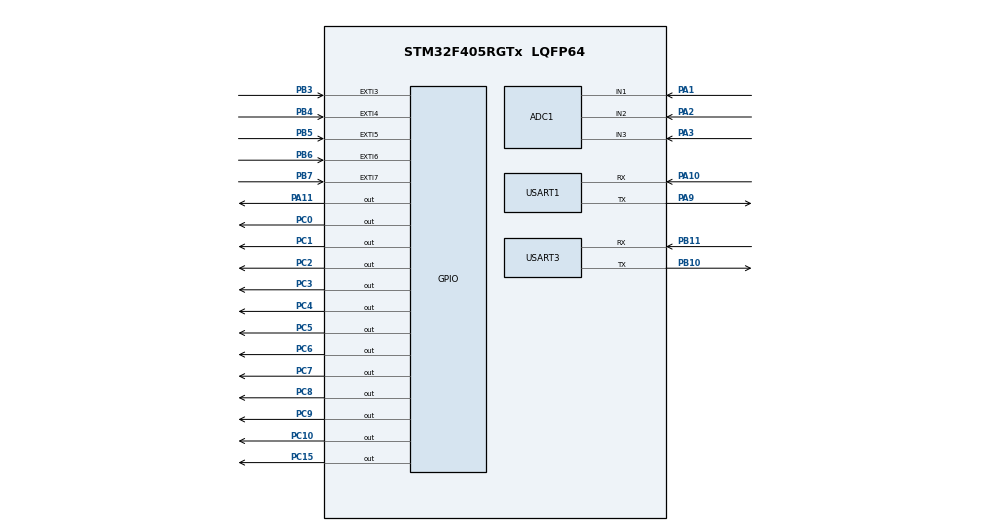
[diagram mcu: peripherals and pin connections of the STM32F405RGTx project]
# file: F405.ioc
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ADC1.Channel-0\#ChannelRegularConversion=ADC_CHANNEL_1
ADC1.ExternalTrigConv=ADC_EXTERNALTRIGCONV_T3_TRGO
ADC1.NbrOfConversionFlag=1
ADC1.Rank-0\#ChannelRegularConversion=1
ADC1.SamplingTime-0\#ChannelRegularConversion=ADC_SAMPLETIME_3CYCLES
ADC1.ScanConvMode=ENABLE
ADC1.master=1
Dma.ADC1.0.Direction=DMA_PERIPH_TO_MEMORY
Dma.ADC1.0.FIFOMode=DMA_FIFOMODE_DISABLE
Dma.ADC1.0.Instance=DMA2_Stream0
Dma.ADC1.0.MemDataAlignment=DMA_MDATAALIGN_HALFWORD
Dma.ADC1.0.MemInc=DMA_MINC_ENABLE
Dma.ADC1.0.Mode=DMA_NORMAL
Dma.ADC1.0.PeriphDataAlignment=DMA_PDATAALIGN_HALFWORD
Dma.ADC1.0.PeriphInc=DMA_PINC_DISABLE
Dma.ADC1.0.Priority=DMA_PRIORITY_LOW
Dma.Request0=ADC1
Mcu.Family=STM32F4
Mcu.Name=STM32F405RGTx
Mcu.Package=LQFP64
NVIC.DMA2_Stream0_IRQn=true\:0\:0\:false\:false\:true\:false\:true\:true
NVIC.PriorityGroup=NVIC_PRIORITYGROUP_4
PA1.Signal=ADCx_IN1
PA10.Mode=Asynchronous
PA10.Signal=USART1_RX
PA11.Signal=GPIO_Output
PA13.Mode=Serial_Wire
PA13.Signal=SYS_JTMS-SWDIO
PA14.Mode=Serial_Wire
PA14.Signal=SYS_JTCK-SWCLK
PA2.Signal=ADCx_IN2
PA3.Signal=ADCx_IN3
PA9.Mode=Asynchronous
PA9.Signal=USART1_TX
PB10.Mode=Asynchronous
PB10.Signal=USART3_TX
PB11.Mode=Asynchronous
PB11.Signal=USART3_RX
PB3.Signal=GPXTI3
PB4.Signal=GPXTI4
PB5.Signal=GPXTI5
PB6.Signal=GPXTI6
PB7.Signal=GPXTI7
PC0.Signal=GPIO_Output
PC1.Signal=GPIO_Output
PC10.Signal=GPIO_Output
PC15-OSC32_OUT.Signal=GPIO_Output
PC2.Signal=GPIO_Output
PC3.Signal=GPIO_Output
PC4.Signal=GPIO_Output
PC5.Signal=GPIO_Output
PC6.Signal=GPIO_Output
PC7.Signal=GPIO_Output
PC8.Signal=GPIO_Output
PC9.Signal=GPIO_Output
ProjectManager.HeapSize=0x200
ProjectManager.StackSize=0x400
ProjectManager.TargetToolchain=STM32CubeIDE
RCC.48MHZClocksFreq_Value=84000000
RCC.AHBFreq_Value=168000000
RCC.APB1CLKDivider=RCC_HCLK_DIV4
RCC.APB1Freq_Value=42000000
RCC.APB1TimFreq_Value=84000000
RCC.APB2CLKDivider=RCC_HCLK_DIV2
RCC.APB2Freq_Value=84000000
RCC.APB2TimFreq_Value=168000000
RCC.CortexFreq_Value=168000000
RCC.HCLKFreq_Value=168000000
RCC.HSE_VALUE=25000000
RCC.HSI_VALUE=16000000
RCC.LSE_VALUE=32768
RCC.PLLM=8
RCC.PLLN=168
RCC.SYSCLKFreq_VALUE=168000000
RCC.SYSCLKSource=RCC_SYSCLKSOURCE_PLLCLK
RCC.VCOOutputFreq_Value=336000000
SH.ADCx_IN1.0=ADC1_IN1,IN1
SH.ADCx_IN2.0=ADC1_IN2,IN2
SH.ADCx_IN3.0=ADC3_IN3
SH.ADCx_IN3.1=ADC1_IN3,IN3
TIM3.Channel-Output\ Compare1\ No\ Output=TIM_CHANNEL_1
USART1.VirtualMode=VM_ASYNC
USART3.VirtualMode=VM_ASYNC
VP_TIM3_VS_no_output1.Mode=Output Compare1 No Output
VP_TIM7_VS_ClockSourceINT.Mode=Enable_Timer
VP_TIM7_VS_OPM.Mode=OPM_bit
board=custom

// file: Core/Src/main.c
/* USER CODE BEGIN Header */
/**
 ******************************************************************************
 * @file           : main.c
 * @brief          : Main program body
 ******************************************************************************
 * @attention
 *
 * Copyright (c) 2023 STMicroelectronics.
 * All rights reserved.
 *
 * This software is licensed under terms that can be found in the LICENSE file
 * in the root directory of this software component.
 * If no LICENSE file comes with this software, it is provided AS-IS.
 *
 ******************************************************************************
 */
/* USER CODE END Header */
#include "main.h"

#include "Display/display.h"
/* USER CODE BEGIN Includes */
#include "MoveControl/movecontrol.h"
#include "Modbus/modbus.h"
#include "Settings/Settings.h"
#include "VibroSens/vibro.h"
/* USER CODE END Includes */

ADC_HandleTypeDef hadc1;
DMA_HandleTypeDef hdma_adc1;

TIM_HandleTypeDef htim3;
TIM_HandleTypeDef htim7;

UART_HandleTypeDef huart1;
UART_HandleTypeDef huart3;

void SystemClock_Config(void);
static void MX_GPIO_Init(void);
static void MX_DMA_Init(void);
static void MX_USART1_UART_Init(void);
static void MX_USART3_UART_Init(void);
static void MX_ADC1_Init(void);
static void MX_TIM3_Init(void);
static void MX_TIM7_Init(void);

int main(void)
{

	/* MCU Configuration--------------------------------------------------------*/

	/* Reset of all peripherals, Initializes the Flash interface and the Systick. */
	HAL_Init();

	/* Configure the system clock */
	SystemClock_Config();

	/* Initialize all configured peripherals */
	MX_GPIO_Init();
	MX_DMA_Init();
	MX_USART1_UART_Init();
	MX_USART3_UART_Init();
	MX_ADC1_Init();
	MX_TIM3_Init();
	MX_TIM7_Init();
	/* USER CODE BEGIN 2 */

	ModBusInit();
	InitMotors();
	LCD1602_Init();
	ReadSettings();
	InitVibro();
	//Старт АЦП
	/* USER CODE END 2 */

	/* Infinite loop */
	/* USER CODE BEGIN WHILE */
	while (1)
	{
		DisplayProc(); //Регистрация нажатия кнопок и вывод инфы
		VibroProc();   //Обработка с датчиков и анализ скорости
		MotorsControlProc(); //Работа с частотниками в соотвеститвии с настрйоками и анализа с датчиков
		/* USER CODE END WHILE */

	}
}

void SystemClock_Config(void)
{
	RCC_OscInitTypeDef RCC_OscInitStruct = {0};
	RCC_ClkInitTypeDef RCC_ClkInitStruct = {0};

	/** Configure the main internal regulator output voltage
	 */
	__HAL_RCC_PWR_CLK_ENABLE();
	__HAL_PWR_VOLTAGESCALING_CONFIG(PWR_REGULATOR_VOLTAGE_SCALE1);

	/** Initializes the RCC Oscillators according to the specified parameters
	 * in the RCC_OscInitTypeDef structure.
	 */
	RCC_OscInitStruct.OscillatorType = RCC_OSCILLATORTYPE_HSI;
	RCC_OscInitStruct.HSIState = RCC_HSI_ON;
	RCC_OscInitStruct.HSICalibrationValue = RCC_HSICALIBRATION_DEFAULT;
	RCC_OscInitStruct.PLL.PLLState = RCC_PLL_NONE;
	if (HAL_RCC_OscConfig(&RCC_OscInitStruct) != HAL_OK)
	{
		Error_Handler();
	}

	/** Initializes the CPU, AHB and APB buses clocks
	 */
	RCC_ClkInitStruct.ClockType = RCC_CLOCKTYPE_HCLK|RCC_CLOCKTYPE_SYSCLK
			|RCC_CLOCKTYPE_PCLK1|RCC_CLOCKTYPE_PCLK2;
	RCC_ClkInitStruct.SYSCLKSource = RCC_SYSCLKSOURCE_HSI;
	RCC_ClkInitStruct.AHBCLKDivider = RCC_SYSCLK_DIV1;
	RCC_ClkInitStruct.APB1CLKDivider = RCC_HCLK_DIV1;
	RCC_ClkInitStruct.APB2CLKDivider = RCC_HCLK_DIV1;

	if (HAL_RCC_ClockConfig(&RCC_ClkInitStruct, FLASH_LATENCY_0) != HAL_OK)
	{
		Error_Handler();
	}
}

static void MX_ADC1_Init(void)
{

	ADC_ChannelConfTypeDef sConfig = {0};

	/** Configure the global features of the ADC (Clock, Resolution, Data Alignment and number of conversion)
	 */
	hadc1.Instance = ADC1;
	hadc1.Init.ClockPrescaler = ADC_CLOCK_SYNC_PCLK_DIV2;
	hadc1.Init.Resolution = ADC_RESOLUTION_12B;
	hadc1.Init.ScanConvMode = ENABLE;
	hadc1.Init.ContinuousConvMode = DISABLE;
	hadc1.Init.DiscontinuousConvMode = DISABLE;
	hadc1.Init.ExternalTrigConvEdge = ADC_EXTERNALTRIGCONVEDGE_RISING;
	hadc1.Init.ExternalTrigConv = ADC_EXTERNALTRIGCONV_T3_TRGO;
	hadc1.Init.DataAlign = ADC_DATAALIGN_RIGHT;
	hadc1.Init.NbrOfConversion = 1;
	hadc1.Init.DMAContinuousRequests = DISABLE;
	hadc1.Init.EOCSelection = ADC_EOC_SINGLE_CONV;
	if (HAL_ADC_Init(&hadc1) != HAL_OK)
	{
		Error_Handler();
	}

	/** Configure for the selected ADC regular channel its corresponding rank in the sequencer and its sample time.
	 */
	sConfig.Channel = ADC_CHANNEL_1;
	sConfig.Rank = 1;
	sConfig.SamplingTime = ADC_SAMPLETIME_3CYCLES;
	if (HAL_ADC_ConfigChannel(&hadc1, &sConfig) != HAL_OK)
	{
		Error_Handler();
	}

}

static void MX_TIM3_Init(void)
{

	TIM_MasterConfigTypeDef sMasterConfig = {0};
	TIM_OC_InitTypeDef sConfigOC = {0};

	htim3.Instance = TIM3;
	htim3.Init.Prescaler = 0;
	htim3.Init.CounterMode = TIM_COUNTERMODE_UP;
	htim3.Init.Period = 65535;
	htim3.Init.ClockDivision = TIM_CLOCKDIVISION_DIV1;
	htim3.Init.AutoReloadPreload = TIM_AUTORELOAD_PRELOAD_DISABLE;
	if (HAL_TIM_OC_Init(&htim3) != HAL_OK)
	{
		Error_Handler();
	}
	sMasterConfig.MasterOutputTrigger = TIM_TRGO_RESET;
	sMasterConfig.MasterSlaveMode = TIM_MASTERSLAVEMODE_DISABLE;
	if (HAL_TIMEx_MasterConfigSynchronization(&htim3, &sMasterConfig) != HAL_OK)
	{
		Error_Handler();
	}
	sConfigOC.OCMode = TIM_OCMODE_TIMING;
	sConfigOC.Pulse = 0;
	sConfigOC.OCPolarity = TIM_OCPOLARITY_HIGH;
	sConfigOC.OCFastMode = TIM_OCFAST_DISABLE;
	if (HAL_TIM_OC_ConfigChannel(&htim3, &sConfigOC, TIM_CHANNEL_1) != HAL_OK)
	{
		Error_Handler();
	}

}

static void MX_TIM7_Init(void)
{

	TIM_MasterConfigTypeDef sMasterConfig = {0};

	htim7.Instance = TIM7;
	htim7.Init.Prescaler = 0;
	htim7.Init.CounterMode = TIM_COUNTERMODE_UP;
	htim7.Init.Period = 65535;
	htim7.Init.AutoReloadPreload = TIM_AUTORELOAD_PRELOAD_DISABLE;
	if (HAL_TIM_Base_Init(&htim7) != HAL_OK)
	{
		Error_Handler();
	}
	if (HAL_TIM_OnePulse_Init(&htim7, TIM_OPMODE_SINGLE) != HAL_OK)
	{
		Error_Handler();
	}
	sMasterConfig.MasterOutputTrigger = TIM_TRGO_RESET;
	sMasterConfig.MasterSlaveMode = TIM_MASTERSLAVEMODE_DISABLE;
	if (HAL_TIMEx_MasterConfigSynchronization(&htim7, &sMasterConfig) != HAL_OK)
	{
		Error_Handler();
	}

}

static void MX_USART1_UART_Init(void)
{

	huart1.Instance = USART1;
	huart1.Init.BaudRate = 115200;
	huart1.Init.WordLength = UART_WORDLENGTH_8B;
	huart1.Init.StopBits = UART_STOPBITS_1;
	huart1.Init.Parity = UART_PARITY_NONE;
	huart1.Init.Mode = UART_MODE_TX_RX;
	huart1.Init.HwFlowCtl = UART_HWCONTROL_NONE;
	huart1.Init.OverSampling = UART_OVERSAMPLING_16;
	if (HAL_UART_Init(&huart1) != HAL_OK)
	{
		Error_Handler();
	}

}

static void MX_USART3_UART_Init(void)
{

	huart3.Instance = USART3;
	huart3.Init.BaudRate = 115200;
	huart3.Init.WordLength = UART_WORDLENGTH_8B;
	huart3.Init.StopBits = UART_STOPBITS_1;
	huart3.Init.Parity = UART_PARITY_NONE;
	huart3.Init.Mode = UART_MODE_TX_RX;
	huart3.Init.HwFlowCtl = UART_HWCONTROL_NONE;
	huart3.Init.OverSampling = UART_OVERSAMPLING_16;
	if (HAL_UART_Init(&huart3) != HAL_OK)
	{
		Error_Handler();
	}

}

static void MX_DMA_Init(void)
{

	/* DMA controller clock enable */
	__HAL_RCC_DMA2_CLK_ENABLE();

	/* DMA interrupt init */
	/* DMA2_Stream0_IRQn interrupt configuration */
	HAL_NVIC_SetPriority(DMA2_Stream0_IRQn, 0, 0);
	HAL_NVIC_EnableIRQ(DMA2_Stream0_IRQn);

}

static void MX_GPIO_Init(void)
{
	GPIO_InitTypeDef GPIO_InitStruct = {0};

	/* GPIO Ports Clock Enable */
	__HAL_RCC_GPIOC_CLK_ENABLE();
	__HAL_RCC_GPIOA_CLK_ENABLE();
	__HAL_RCC_GPIOB_CLK_ENABLE();

	/*Configure GPIO pin Output Level */
	HAL_GPIO_WritePin(GPIOC, GPIO_PIN_15|GPIO_PIN_0|GPIO_PIN_1|GPIO_PIN_2
			|GPIO_PIN_3|GPIO_PIN_4|GPIO_PIN_5|GPIO_PIN_6
			|GPIO_PIN_7|GPIO_PIN_8|GPIO_PIN_9|GPIO_PIN_10, GPIO_PIN_RESET);

	/*Configure GPIO pin Output Level */
	HAL_GPIO_WritePin(GPIOA, GPIO_PIN_11, GPIO_PIN_RESET);

	/*Configure GPIO pins : PC15 PC0 PC1 PC2
                           PC3 PC4 PC5 PC6
                           PC7 PC8 PC9 PC10 */
	GPIO_InitStruct.Pin = GPIO_PIN_15|GPIO_PIN_0|GPIO_PIN_1|GPIO_PIN_2
			|GPIO_PIN_3|GPIO_PIN_4|GPIO_PIN_5|GPIO_PIN_6
			|GPIO_PIN_7|GPIO_PIN_8|GPIO_PIN_9|GPIO_PIN_10;
	GPIO_InitStruct.Mode = GPIO_MODE_OUTPUT_PP;
	GPIO_InitStruct.Pull = GPIO_NOPULL;
	GPIO_InitStruct.Speed = GPIO_SPEED_FREQ_LOW;
	HAL_GPIO_Init(GPIOC, &GPIO_InitStruct);

	/*Configure GPIO pin : PA3 */
	GPIO_InitStruct.Pin = GPIO_PIN_3;
	GPIO_InitStruct.Mode = GPIO_MODE_ANALOG;
	GPIO_InitStruct.Pull = GPIO_NOPULL;
	HAL_GPIO_Init(GPIOA, &GPIO_InitStruct);

	/*Configure GPIO pin : PA11 */
	GPIO_InitStruct.Pin = GPIO_PIN_11;
	GPIO_InitStruct.Mode = GPIO_MODE_OUTPUT_PP;
	GPIO_InitStruct.Pull = GPIO_NOPULL;
	GPIO_InitStruct.Speed = GPIO_SPEED_FREQ_LOW;
	HAL_GPIO_Init(GPIOA, &GPIO_InitStruct);

	/*Configure GPIO pins : PB3 PB4 PB5 PB6
                           PB7 */
	GPIO_InitStruct.Pin = GPIO_PIN_3|GPIO_PIN_4|GPIO_PIN_5|GPIO_PIN_6
			|GPIO_PIN_7;
	GPIO_InitStruct.Mode = GPIO_MODE_IT_RISING;
	GPIO_InitStruct.Pull = GPIO_NOPULL;
	HAL_GPIO_Init(GPIOB, &GPIO_InitStruct);

}

void Error_Handler(void)
{
	__disable_irq();
	while (1)
	{
	}
}
